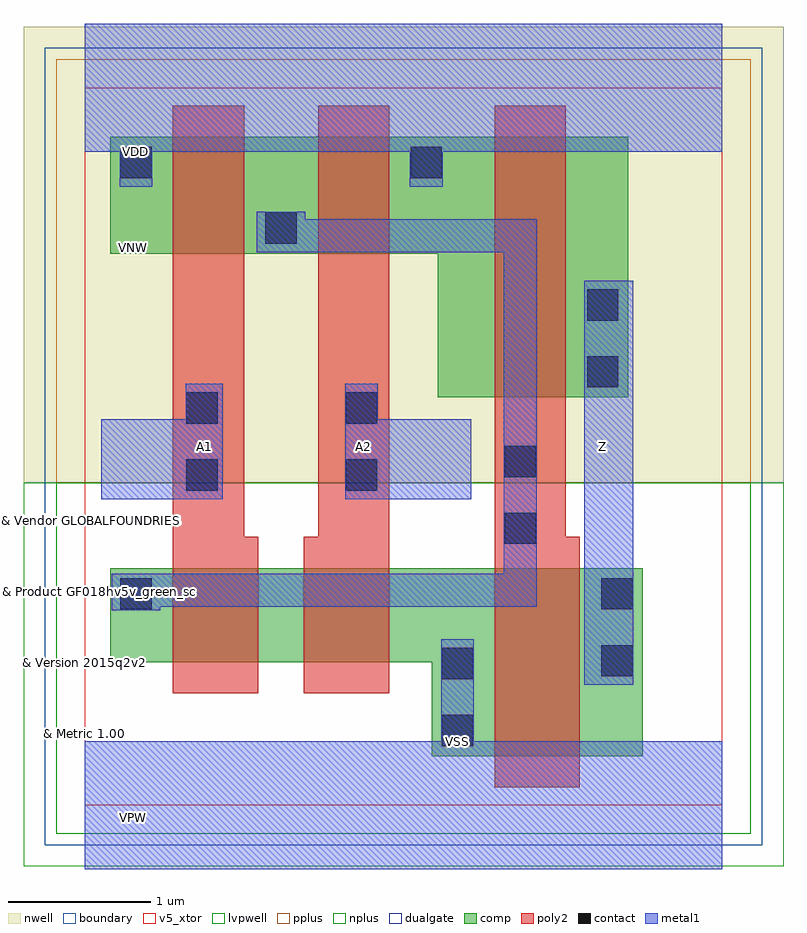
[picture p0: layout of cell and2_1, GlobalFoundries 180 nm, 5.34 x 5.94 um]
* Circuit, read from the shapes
.subckt and2_1 A1 A2 VDD VNW VSS Z
XM1 n1 A1 n2 VSUBS nfet_05v0 w=0.66u l=0.6u
XM2 VSS A2 n1 VSUBS nfet_05v0 w=0.66u l=0.6u
XM3 Z n2 VSS VSUBS nfet_05v0 w=1.32u l=0.6u
XM4 n2 A1 VDD VNW pfet_05v0 w=0.82u l=0.5u
XM5 VDD A2 n2 VNW pfet_05v0 w=0.82u l=0.5u
XM6 Z n2 VDD VNW pfet_05v0 w=1.83u l=0.5u
.ends

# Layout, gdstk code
import gdstk
lib = gdstk.Library(unit=1e-6, precision=1e-09)
def R(c, l, rs):  # rectangles x0, y0, x1, y1
    for r in rs: c.add(gdstk.rectangle(r[:2], r[2:], *l))
def P(c, l, *ps):  # polygons
    for p in ps: c.add(gdstk.Polygon(p, *l))
boundary = (0, 0)
nwell = (21, 0)
comp = (22, 0)
poly2 = (30, 0)
pplus = (31, 0)
nplus = (32, 0)
contact = (33, 0)
metal1 = (34, 0)
dualgate = (55, 0)
v5_xtor = (112, 1)
lvpwell = (204, 0)

and2_1 = lib.new_cell('and2_1')
R(and2_1, boundary, [(12.4,17.1,16.88,22.14)])
R(and2_1, nwell, [(11.97,19.365,17.31,22.57)])
P(and2_1, comp, [(14.88,19.965),(14.88,20.975),(12.58,20.975),(12.58,21.795),(16.22,21.795),(16.22,19.965)],
  [(14.84,17.445),(14.84,18.105),(12.58,18.105),(12.58,18.765),(16.32,18.765),(16.32,17.445)])
P(and2_1, poly2, [(13.02,17.885),(13.02,22.015),(13.52,22.015),(13.52,18.985),(13.62,18.985),(13.62,17.885)],
  [(13.94,17.885),(13.94,18.985),(14.04,18.985),(14.04,22.015),(14.54,22.015),(14.54,17.885)],
  [(15.28,17.225),(15.28,22.015),(15.78,22.015),(15.78,18.985),(15.88,18.985),(15.88,17.225)])
R(and2_1, pplus, [(12.2,19.365,17.08,22.34)])
R(and2_1, nplus, [(12.2,16.9,17.08,19.365)])
R(and2_1, contact, [(14.91,17.515,15.13,17.735), (14.91,17.985,15.13,18.205), (16.03,18.005,16.25,18.225), (12.65,18.475,12.87,18.695), (16.03,18.475,16.25,18.695), (15.35,18.935,15.57,19.155), (13.115,19.31,13.335,19.53), (14.235,19.31,14.455,19.53), (15.35,19.405,15.57,19.625), (13.115,19.78,13.335,20), (14.235,19.78,14.455,20), (15.93,20.035,16.15,20.255), (15.93,20.505,16.15,20.725), (13.67,21.045,13.89,21.265), (12.65,21.505,12.87,21.725), (14.69,21.505,14.91,21.725)])
R(and2_1, metal1, [(15.91,17.945,16.255,20.785)])
P(and2_1, metal1, [(12.515,19.25),(12.515,19.81),(13.11,19.81),(13.11,20.06),(13.37,20.06),(13.37,19.25)],
  [(14.23,19.25),(14.23,20.06),(14.46,20.06),(14.46,19.81),(15.115,19.81),(15.115,19.25)],
  [(12.59,18.47),(12.59,18.725),(15.345,18.725),(15.345,20.985),(13.61,20.985),(13.61,21.27),(13.95,21.27),(13.95,21.215),(15.575,21.215),(15.575,18.495),(12.93,18.495),(12.93,18.47)],
  [(12.4,16.65),(12.4,17.55),(14.905,17.55),(14.905,18.265),(15.135,18.265),(15.135,17.55),(16.88,17.55),(16.88,16.65)],
  [(12.645,21.445),(12.645,21.69),(12.4,21.69),(12.4,22.59),(16.88,22.59),(16.88,21.69),(14.915,21.69),(14.915,21.445),(14.685,21.445),(14.685,21.69),(12.875,21.69),(12.875,21.445)])
R(and2_1, dualgate, [(12.12,16.82,17.16,22.42)])
R(and2_1, v5_xtor, [(12.4,17.1,16.88,22.14)])
R(and2_1, lvpwell, [(11.97,16.67,17.31,19.365)])
and2_1.add(gdstk.Label('A1', (13.24,19.62), layer=34, texttype=10))
and2_1.add(gdstk.Label('A2', (14.36,19.62), layer=34, texttype=10))
and2_1.add(gdstk.Label('VDD', (12.76,21.69), layer=34, texttype=10))
and2_1.add(gdstk.Label('VSS', (15.02,17.55), layer=34, texttype=10))
and2_1.add(gdstk.Label('Z', (16.04,19.62), layer=34, texttype=10))
and2_1.add(gdstk.Label('& Vendor GLOBALFOUNDRIES', (12.4,19.1), layer=63, texttype=63))
and2_1.add(gdstk.Label('& Product GF018hv5v_green_sc9', (12.4,18.6), layer=63, texttype=63))
and2_1.add(gdstk.Label('& Version 2015q2v2', (12.4,18.1), layer=63, texttype=63))
and2_1.add(gdstk.Label('& Metric 1.00', (12.4,17.6), layer=63, texttype=63))
and2_1.add(gdstk.Label('VNW', (12.745,21.02), layer=21, texttype=10))
and2_1.add(gdstk.Label('VPW', (12.74,17.015), layer=204, texttype=10))

lib.write_gds('and2_1.gds')
